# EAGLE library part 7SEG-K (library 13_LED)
7-segment LED Cathode Common

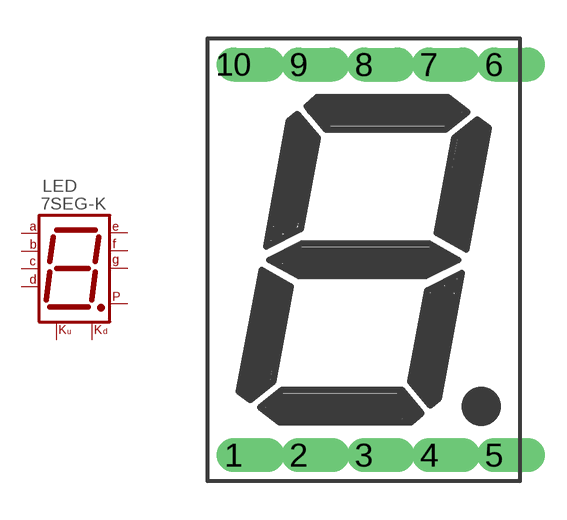
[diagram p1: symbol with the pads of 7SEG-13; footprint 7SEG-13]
Designator prefix LED

## 7SEG-K  [7SEG-13]
1  E  pas
2  D  pas
3  CK2  pas
4  C  pas
5  DP  pas
6  B  pas
7  A  pas
8  CK1  pas
9  F  pas
10  G  pas

## Footprint 7SEG-13 (pad centres in mm)
7-segment LED 13 mm
drill 0.813 offset: 1 -5.08,-7.62; 2 -2.54,-7.62; 3 0,-7.62; 4 2.54,-7.62; 5 5.08,-7.62; 6 5.08,7.62; 7 2.54,7.62; 8 0,7.62; 9 -2.54,7.62; 10 -5.08,7.62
